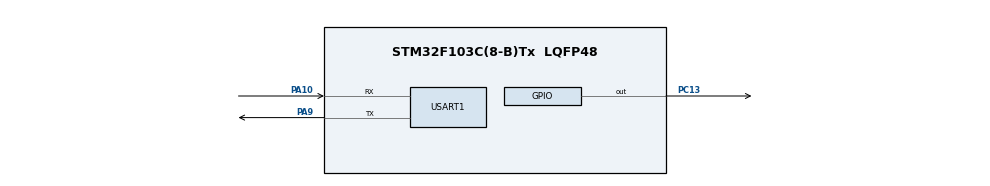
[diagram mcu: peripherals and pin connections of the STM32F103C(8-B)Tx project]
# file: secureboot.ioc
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Mcu.Family=STM32F1
Mcu.Name=STM32F103C(8-B)Tx
Mcu.Package=LQFP48
NVIC.PriorityGroup=NVIC_PRIORITYGROUP_4
NVIC.USART1_IRQn=true\:0\:0\:false\:false\:true\:true\:true\:true
PA10.Mode=Asynchronous
PA10.Signal=USART1_RX
PA13.Mode=Serial_Wire
PA13.Signal=SYS_JTMS-SWDIO
PA14.Mode=Serial_Wire
PA14.Signal=SYS_JTCK-SWCLK
PA9.Mode=Asynchronous
PA9.Signal=USART1_TX
PC13-TAMPER-RTC.Signal=GPIO_Output
ProjectManager.HeapSize=0x200
ProjectManager.StackSize=0x400
ProjectManager.TargetToolchain=CMake
RCC.APB1Freq_Value=8000000
RCC.APB2Freq_Value=8000000
USART1.VirtualMode=VM_ASYNC
VP_WWDG_VS_WWDG.Mode=WWDG_Activate
board=custom

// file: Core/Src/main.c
/* USER CODE BEGIN Header */
/**
  ******************************************************************************
  * @file           : main.c
  * @brief          : Main program body
  ******************************************************************************
  * @attention
  *
  * Copyright (c) 2026 STMicroelectronics.
  * All rights reserved.
  *
  * This software is licensed under terms that can be found in the LICENSE file
  * in the root directory of this software component.
  * If no LICENSE file comes with this software, it is provided AS-IS.
  *
  ******************************************************************************
  */
/* USER CODE END Header */
#include "main.h"

/* USER CODE BEGIN Includes */
#include "boot_controller.h"
#include "log.h"
#include "comm_manager.h"
#include "my_packer.h"
/* USER CODE END Includes */

UART_HandleTypeDef huart1;

WWDG_HandleTypeDef hwwdg;

/* USER CODE BEGIN PV */
CommManager_t uart1Com;
boot_controller_t bootController;
static uint8_t receiveByte;
Packer_t uartPacker = {
    .pack = my_pack_data,
    .unpack = my_unpack_data_state,
};

/* USER CODE END PV */

void SystemClock_Config(void);
/**
  * @brief Initialize GPIO pins used by the bootloader board support code.
  */
static void MX_GPIO_Init(void);
/**
  * @brief Initialize USART1 for bootloader UART communication.
  */
static void MX_USART1_UART_Init(void);
// static void MX_WWDG_Init(void);

/* USER CODE BEGIN 0 */

/**
  * @brief HAL RX-complete callback for USART1.
  *
  * @param[in] huart UART handle supplied by HAL.
  *
  * @post Queues the received byte into the communication manager and rearms
  *       interrupt-driven reception for the next byte.
  */
void HAL_UART_RxCpltCallback(UART_HandleTypeDef *huart)
{
  if (huart->Instance == USART1)
  {
    onReceiveData(&uart1Com, &receiveByte, 1U);
//    GPIOC->BSRR = (1 << 13);
    HAL_UART_Receive_IT(&huart1, (uint8_t *)&receiveByte, 1); // Wait for the next byte.
  }
}

/**
  * @brief HAL TX-complete callback for USART1.
  *
  * @param[in] huart UART handle supplied by HAL.
  *
  * @post Clears the communication manager TX-in-progress flag.
  */
void HAL_UART_TxCpltCallback(UART_HandleTypeDef *huart)
{
  if (huart->Instance == USART1)
  {
    onSendDone(&uart1Com);
  }
}

/**
  * @brief Start a non-blocking USART1 transmit operation.
  *
  * @param[in] buff Bytes to transmit.
  * @param[in] length Number of bytes to transmit.
  *
  * @return true when HAL accepted the interrupt-driven transmit request.
  * @return false when HAL_UART_Transmit_IT returned an error.
  */
static bool uart_send(const uint8_t *buff, uint16_t length)
{
  return HAL_UART_Transmit_IT(&huart1, buff, length) == HAL_OK;
}

/**
  * @brief Forward one decoded UART payload to the boot controller.
  *
  * @param[in] data Decoded payload buffer.
  * @param[in] length Payload length in bytes.
  */
static void receive_callback(uint8_t *data, uint16_t length)
{
  boot_controller_on_packet(&bootController, data, length);
}

/**
  * @brief Forward a communication/parser failure to the boot controller.
  *
  * @param[in] error Parser or communication error code.
  */
static void receive_fail_callback(uint8_t error)
{
  boot_controller_on_parser_error(&bootController, error);
}

// static int test_ecdsa_p256(void)
// {
//   uint8_t public_key[ECDSA_P256_PUBLIC_KEY_SIZE];
//   uint8_t digest[SHA256_DIGEST_SIZE];
//   uint8_t signature[ECDSA_P256_SIGNATURE_SIZE];
//   ecdsa_p256_verify_digest(public_key, digest, signature);

//   return 0;
// }

/* USER CODE END 0 */

int main(void)
{

  /* MCU Configuration--------------------------------------------------------*/

  /* Reset of all peripherals, Initializes the Flash interface and the Systick. */
  HAL_Init();

  /* Configure the system clock */
  SystemClock_Config();

  /* USER CODE BEGIN SysInit */
  log_init();
  /* USER CODE END SysInit */

  /* Initialize all configured peripherals */
  MX_GPIO_Init();
  MX_USART1_UART_Init();
  // MX_WWDG_Init();
  /* USER CODE BEGIN 2 */
  if (comm_manager_init(&uart1Com, &uartPacker, receive_callback,
                        receive_fail_callback, uart_send) != COMM_MANAGER_SUCCESS)
  {
    Error_Handler();
  }
  boot_controller_init(&bootController, &uart1Com);
  if (HAL_UART_Receive_IT(&huart1, &receiveByte, 1U) != HAL_OK)
  {
    Error_Handler();
  }

  /* USER CODE END 2 */
  log_println("Bootloader started.");
  /* Infinite loop */
  while (1)
  {
    comm_control(&uart1Com);
    boot_controller_poll(&bootController);
    /* USER CODE BEGIN 3 */
    // HAL_WWDG_Refresh(&hwwdg);
  }
  /* USER CODE END 3 */
}

void SystemClock_Config(void)
{
  RCC_OscInitTypeDef RCC_OscInitStruct = {0};
  RCC_ClkInitTypeDef RCC_ClkInitStruct = {0};

  /** Initializes the RCC Oscillators according to the specified parameters
  * in the RCC_OscInitTypeDef structure.
  */
  RCC_OscInitStruct.OscillatorType = RCC_OSCILLATORTYPE_HSI;
  RCC_OscInitStruct.HSIState = RCC_HSI_ON;
  RCC_OscInitStruct.HSICalibrationValue = RCC_HSICALIBRATION_DEFAULT;
  RCC_OscInitStruct.PLL.PLLState = RCC_PLL_ON;
  RCC_OscInitStruct.PLL.PLLSource = RCC_PLLSOURCE_HSI_DIV2;
  RCC_OscInitStruct.PLL.PLLMUL = RCC_PLL_MUL16;
  if (HAL_RCC_OscConfig(&RCC_OscInitStruct) != HAL_OK)
  {
    Error_Handler();
  }

  /** Initializes the CPU, AHB and APB buses clocks
  */
  RCC_ClkInitStruct.ClockType = RCC_CLOCKTYPE_HCLK|RCC_CLOCKTYPE_SYSCLK
                              |RCC_CLOCKTYPE_PCLK1|RCC_CLOCKTYPE_PCLK2;
  RCC_ClkInitStruct.SYSCLKSource = RCC_SYSCLKSOURCE_PLLCLK;
  RCC_ClkInitStruct.AHBCLKDivider = RCC_SYSCLK_DIV1;
  RCC_ClkInitStruct.APB1CLKDivider = RCC_HCLK_DIV2;
  RCC_ClkInitStruct.APB2CLKDivider = RCC_HCLK_DIV1;

  if (HAL_RCC_ClockConfig(&RCC_ClkInitStruct, FLASH_LATENCY_2) != HAL_OK)
  {
    Error_Handler();
  }
}

static void MX_USART1_UART_Init(void)
{

  huart1.Instance = USART1;
  huart1.Init.BaudRate = 115200;
  huart1.Init.WordLength = UART_WORDLENGTH_8B;
  huart1.Init.StopBits = UART_STOPBITS_1;
  huart1.Init.Parity = UART_PARITY_NONE;
  huart1.Init.Mode = UART_MODE_TX_RX;
  huart1.Init.HwFlowCtl = UART_HWCONTROL_NONE;
  huart1.Init.OverSampling = UART_OVERSAMPLING_16;
  if (HAL_UART_Init(&huart1) != HAL_OK)
  {
    Error_Handler();
  }

}

static void MX_WWDG_Init(void)
{

  hwwdg.Instance = WWDG;
  hwwdg.Init.Prescaler = WWDG_PRESCALER_1;
  hwwdg.Init.Window = 64;
  hwwdg.Init.Counter = 64;
  hwwdg.Init.EWIMode = WWDG_EWI_DISABLE;
  if (HAL_WWDG_Init(&hwwdg) != HAL_OK)
  {
    Error_Handler();
  }

}

static void MX_GPIO_Init(void)
{
  GPIO_InitTypeDef GPIO_InitStruct = {0};

  /* GPIO Ports Clock Enable */
  __HAL_RCC_GPIOC_CLK_ENABLE();
  __HAL_RCC_GPIOA_CLK_ENABLE();

  /*Configure GPIO pin Output Level */
  HAL_GPIO_WritePin(GPIOC, GPIO_PIN_13, GPIO_PIN_RESET);

  /*Configure GPIO pin : PC13 */
  GPIO_InitStruct.Pin = GPIO_PIN_13;
  GPIO_InitStruct.Mode = GPIO_MODE_OUTPUT_PP;
  GPIO_InitStruct.Pull = GPIO_NOPULL;
  GPIO_InitStruct.Speed = GPIO_SPEED_FREQ_LOW;
  HAL_GPIO_Init(GPIOC, &GPIO_InitStruct);

}

void Error_Handler(void)
{
  __disable_irq();
  while (1)
  {
  }
}
#ifdef USE_FULL_ASSERT
/**
  * @brief  Reports the name of the source file and the source line number
  *         where the assert_param error has occurred.
  * @param  file: pointer to the source file name
  * @param  line: assert_param error line source number
  * @retval None
  */
void assert_failed(uint8_t *file, uint32_t line)
{
  /* USER CODE BEGIN 6 */
  /* User can add board-specific assert reporting here. */
  /* USER CODE END 6 */
}
#endif /* USE_FULL_ASSERT */
